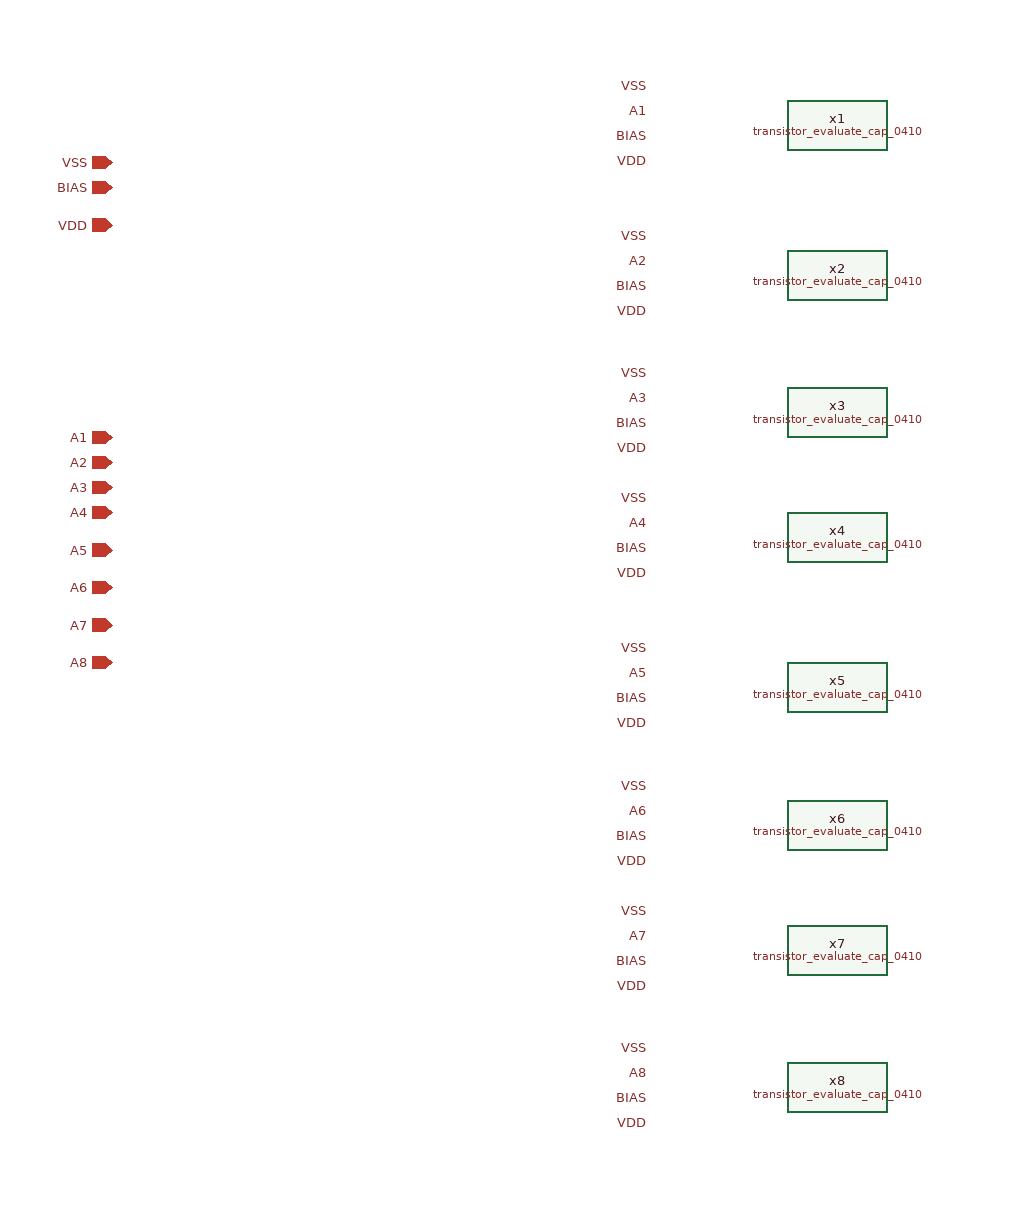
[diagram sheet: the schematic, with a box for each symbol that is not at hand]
v {xschem version=3.4.8RC file_version=1.3}
G {}
K {}
V {}
S {}
F {}
E {}
C {devices/ipin.sym} -430 320 0 0 {name=p1 lab=A2}
C {devices/ipin.sym} -430 340 0 0 {name=p2 lab=A3
}
C {devices/ipin.sym} -430 130 0 0 {name=p7 lab=VDD}
C {devices/ipin.sym} -430 300 0 0 {name=p3 lab=A1}
C {devices/ipin.sym} -430 80 0 0 {name=p11 lab=VSS}
C {devices/ipin.sym} -430 100 0 0 {name=p14 lab=BIAS
}
C {devices/lab_pin.sym} 0 140 0 0 {name=p17 sig_type=std_logic lab=VSS}
C {devices/lab_pin.sym} 0 180 0 0 {name=p26 sig_type=std_logic lab=BIAS}
C {devices/lab_pin.sym} 0 160 0 0 {name=p34 sig_type=std_logic lab=A2}
C {devices/ipin.sym} -430 360 0 0 {name=p42 lab=A4}
C {devices/ipin.sym} -430 390 0 0 {name=p43 lab=A5
}
C {devices/ipin.sym} -430 420 0 0 {name=p44 lab=A6
}
C {devices/ipin.sym} -430 450 0 0 {name=p45 lab=A7
}
C {devices/ipin.sym} -430 480 0 0 {name=p46 lab=A8
}
C {devices/lab_pin.sym} 0 200 0 0 {name=p4 sig_type=std_logic lab=VDD}
C {devices/lab_pin.sym} 0 250 0 0 {name=p5 sig_type=std_logic lab=VSS}
C {devices/lab_pin.sym} 0 290 0 0 {name=p6 sig_type=std_logic lab=BIAS}
C {devices/lab_pin.sym} 0 270 0 0 {name=p8 sig_type=std_logic lab=A3}
C {devices/lab_pin.sym} 0 310 0 0 {name=p9 sig_type=std_logic lab=VDD}
C {devices/lab_pin.sym} 0 350 0 0 {name=p10 sig_type=std_logic lab=VSS}
C {devices/lab_pin.sym} 0 390 0 0 {name=p12 sig_type=std_logic lab=BIAS}
C {devices/lab_pin.sym} 0 370 0 0 {name=p13 sig_type=std_logic lab=A4}
C {devices/lab_pin.sym} 0 410 0 0 {name=p15 sig_type=std_logic lab=VDD}
C {devices/lab_pin.sym} 0 20 0 0 {name=p16 sig_type=std_logic lab=VSS}
C {devices/lab_pin.sym} 0 60 0 0 {name=p18 sig_type=std_logic lab=BIAS}
C {devices/lab_pin.sym} 0 40 0 0 {name=p19 sig_type=std_logic lab=A1}
C {devices/lab_pin.sym} 0 80 0 0 {name=p20 sig_type=std_logic lab=VDD}
C {devices/lab_pin.sym} 0 580 0 0 {name=p21 sig_type=std_logic lab=VSS}
C {devices/lab_pin.sym} 0 620 0 0 {name=p22 sig_type=std_logic lab=BIAS}
C {devices/lab_pin.sym} 0 600 0 0 {name=p23 sig_type=std_logic lab=A6}
C {devices/lab_pin.sym} 0 640 0 0 {name=p24 sig_type=std_logic lab=VDD}
C {devices/lab_pin.sym} 0 680 0 0 {name=p25 sig_type=std_logic lab=VSS}
C {devices/lab_pin.sym} 0 720 0 0 {name=p27 sig_type=std_logic lab=BIAS}
C {devices/lab_pin.sym} 0 700 0 0 {name=p28 sig_type=std_logic lab=A7}
C {devices/lab_pin.sym} 0 740 0 0 {name=p29 sig_type=std_logic lab=VDD}
C {devices/lab_pin.sym} 0 790 0 0 {name=p30 sig_type=std_logic lab=VSS}
C {devices/lab_pin.sym} 0 830 0 0 {name=p31 sig_type=std_logic lab=BIAS}
C {devices/lab_pin.sym} 0 810 0 0 {name=p32 sig_type=std_logic lab=A8}
C {devices/lab_pin.sym} 0 850 0 0 {name=p33 sig_type=std_logic lab=VDD}
C {devices/lab_pin.sym} 0 470 0 0 {name=p35 sig_type=std_logic lab=VSS}
C {devices/lab_pin.sym} 0 510 0 0 {name=p36 sig_type=std_logic lab=BIAS}
C {devices/lab_pin.sym} 0 490 0 0 {name=p37 sig_type=std_logic lab=A5}
C {devices/lab_pin.sym} 0 530 0 0 {name=p38 sig_type=std_logic lab=VDD}
C {transistor_evaluate_cap_0410.sym} 150 50 0 0 {name=x1}
C {transistor_evaluate_cap_0410.sym} 150 170 0 0 {name=x2}
C {transistor_evaluate_cap_0410.sym} 150 280 0 0 {name=x3}
C {transistor_evaluate_cap_0410.sym} 150 380 0 0 {name=x4}
C {transistor_evaluate_cap_0410.sym} 150 500 0 0 {name=x5}
C {transistor_evaluate_cap_0410.sym} 150 610 0 0 {name=x6}
C {transistor_evaluate_cap_0410.sym} 150 710 0 0 {name=x7}
C {transistor_evaluate_cap_0410.sym} 150 820 0 0 {name=x8}
